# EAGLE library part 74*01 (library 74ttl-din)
Quad 2-input NAND gate, open collector

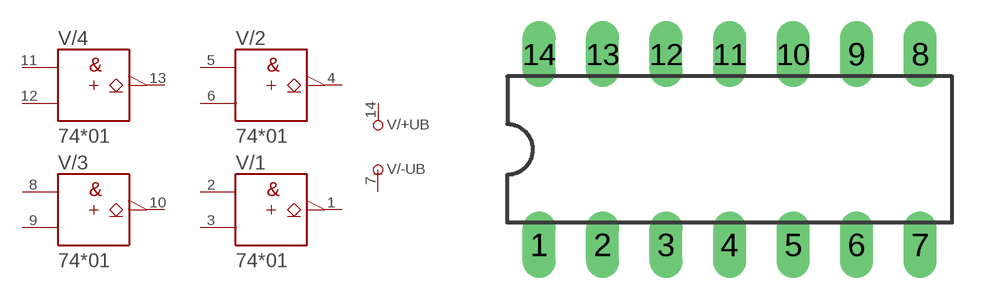
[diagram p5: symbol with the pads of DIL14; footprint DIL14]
Designator prefix V; gates /+UB=+UB /-UB=-UB /1=01 /2=01 /3=01 /4=01

## 7401N  [DIL14]
1  /1:Y  oc
2  /1:A  in
3  /1:B  in
4  /2:Y  oc
5  /2:A  in
6  /2:B  in
7  /-UB:-UB  pwr
8  /3:A  in
9  /3:B  in
10  /3:Y  oc
11  /4:A  in
12  /4:B  in
13  /4:Y  oc
14  /+UB:+UB  pwr

## Footprint DIL14 (pad centres in mm)
Dual In Line Package
drill 0.813 long: 1 -7.62,-3.81; 2 -5.08,-3.81; 3 -2.54,-3.81; 4 0,-3.81; 5 2.54,-3.81; 6 5.08,-3.81; 7 7.62,-3.81; 8 7.62,3.81; 9 5.08,3.81; 10 2.54,3.81; 11 0,3.81; 12 -2.54,3.81; 13 -5.08,3.81; 14 -7.62,3.81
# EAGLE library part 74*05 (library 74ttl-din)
Hex INVERTER, open collector

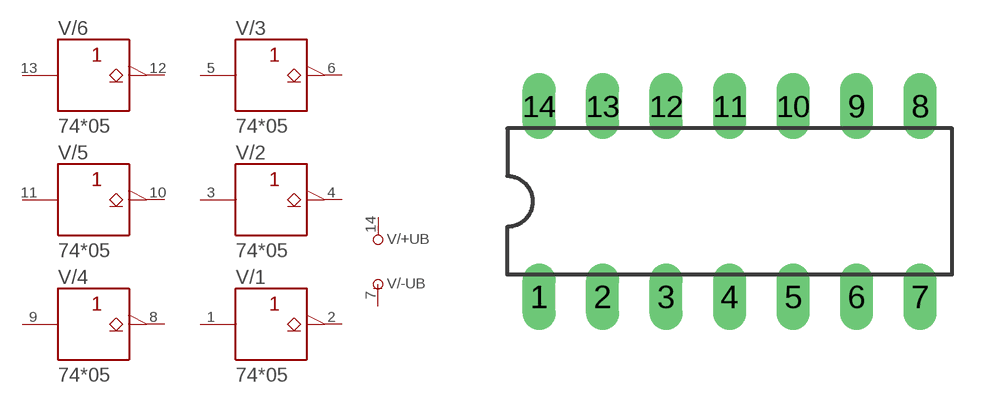
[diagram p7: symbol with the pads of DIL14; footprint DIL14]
Designator prefix V; gates /+UB=+UB /-UB=-UB /1=05 /2=05 /3=05 /4=05 /5=05 /6=05

## 7405N  [DIL14]
1  /1:A  in
2  /1:Y  oc
3  /2:A  in
4  /2:Y  oc
5  /3:A  in
6  /3:Y  oc
7  /-UB:-UB  pwr
8  /4:Y  oc
9  /4:A  in
10  /5:Y  oc
11  /5:A  in
12  /6:Y  oc
13  /6:A  in
14  /+UB:+UB  pwr

## Footprint DIL14 (pad centres in mm)
Dual In Line Package
drill 0.813 long: 1 -7.62,-3.81; 2 -5.08,-3.81; 3 -2.54,-3.81; 4 0,-3.81; 5 2.54,-3.81; 6 5.08,-3.81; 7 7.62,-3.81; 8 7.62,3.81; 9 5.08,3.81; 10 2.54,3.81; 11 0,3.81; 12 -2.54,3.81; 13 -5.08,3.81; 14 -7.62,3.81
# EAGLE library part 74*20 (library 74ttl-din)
Dual 4-input NAND gate

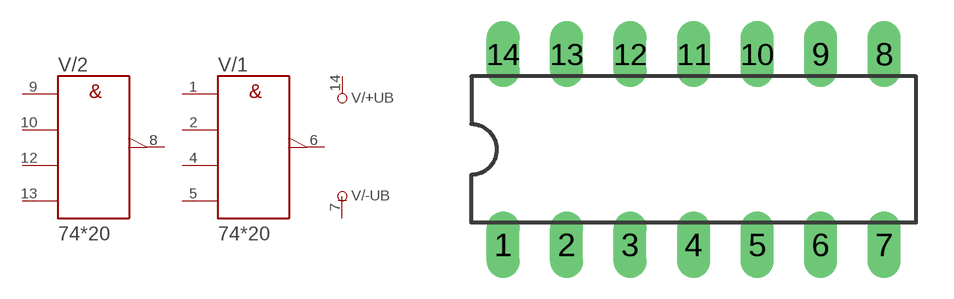
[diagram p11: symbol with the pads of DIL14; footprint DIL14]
Designator prefix V; gates /+UB=+UB /-UB=-UB /1=20 /2=20

## 7420N  [DIL14]
1  /1:A  in
2  /1:B  in
4  /1:C  in
5  /1:D  in
6  /1:Y  out
7  /-UB:-UB  pwr
8  /2:Y  out
9  /2:A  in
10  /2:B  in
12  /2:C  in
13  /2:D  in
14  /+UB:+UB  pwr

## Footprint DIL14 (pad centres in mm)
Dual In Line Package
drill 0.813 long: 1 -7.62,-3.81; 2 -5.08,-3.81; 3 -2.54,-3.81; 4 0,-3.81; 5 2.54,-3.81; 6 5.08,-3.81; 7 7.62,-3.81; 8 7.62,3.81; 9 5.08,3.81; 10 2.54,3.81; 11 0,3.81; 12 -2.54,3.81; 13 -5.08,3.81; 14 -7.62,3.81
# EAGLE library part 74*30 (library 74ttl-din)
8-input NAND gate

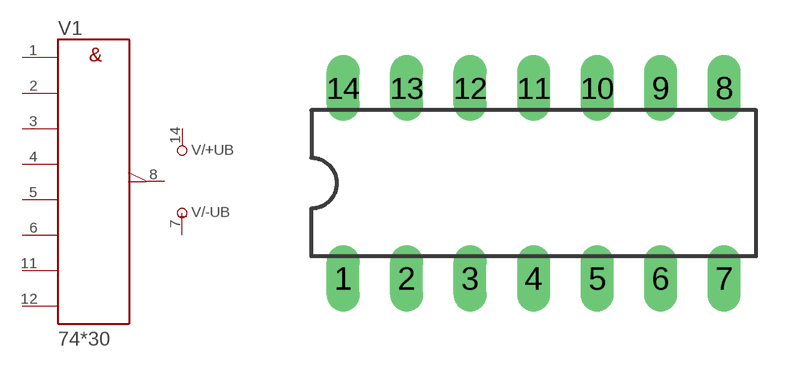
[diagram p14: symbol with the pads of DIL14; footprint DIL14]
Designator prefix V; gates /+UB=+UB /-UB=-UB 1=30

## 7430N  [DIL14]
1  1:A  in
2  1:B  in
3  1:C  in
4  1:D  in
5  1:E  in
6  1:F  in
7  /-UB:-UB  pwr
8  1:Y  out
11  1:G  in
12  1:H  in
14  /+UB:+UB  pwr

## Footprint DIL14 (pad centres in mm)
Dual In Line Package
drill 0.813 long: 1 -7.62,-3.81; 2 -5.08,-3.81; 3 -2.54,-3.81; 4 0,-3.81; 5 2.54,-3.81; 6 5.08,-3.81; 7 7.62,-3.81; 8 7.62,3.81; 9 5.08,3.81; 10 2.54,3.81; 11 0,3.81; 12 -2.54,3.81; 13 -5.08,3.81; 14 -7.62,3.81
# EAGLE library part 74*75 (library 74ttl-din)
4-bit bistable LATCH

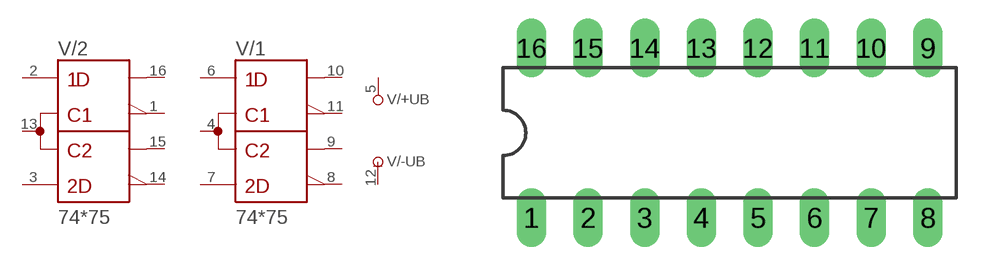
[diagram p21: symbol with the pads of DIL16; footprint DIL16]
Designator prefix V; gates /+UB=+UB /-UB=-UB /1=75 /2=75

## 7475N  [DIL16]
1  /2:!1Q  out
2  /2:1D  in
3  /2:2D  in
4  /1:1C,2C  in
5  /+UB:+UB  pwr
6  /1:1D  in
7  /1:2D  in
8  /1:!2Q  out
9  /1:2Q  out
10  /1:1Q  out
11  /1:!1Q  out
12  /-UB:-UB  pwr
13  /2:1C,2C  in
14  /2:!2Q  out
15  /2:2Q  out
16  /2:1Q  out

## Footprint DIL16 (pad centres in mm)
Dual In Line Package
drill 0.813 long: 1 -8.89,-3.81; 2 -6.35,-3.81; 3 -3.81,-3.81; 4 -1.27,-3.81; 5 1.27,-3.81; 6 3.81,-3.81; 7 6.35,-3.81; 8 8.89,-3.81; 9 8.89,3.81; 10 6.35,3.81; 11 3.81,3.81; 12 1.27,3.81; 13 -1.27,3.81; 14 -3.81,3.81; 15 -6.35,3.81; 16 -8.89,3.81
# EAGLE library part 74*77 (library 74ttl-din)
4-bit D LATCH

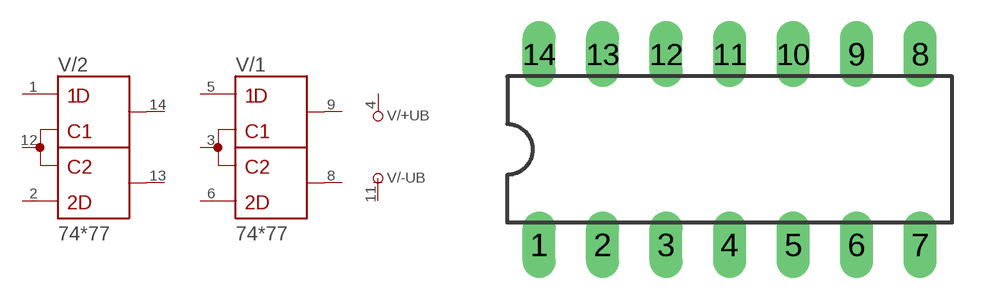
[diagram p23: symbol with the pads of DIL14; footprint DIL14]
Designator prefix V; gates /+UB=+UB /-UB=-UB /1=77 /2=77

## 7477N  [DIL14]
1  /2:1D  in
2  /2:2D  in
3  /1:1C,2C  in
4  /+UB:+UB  pwr
5  /1:1D  in
6  /1:2D  in
8  /1:2Q  out
9  /1:1Q  out
11  /-UB:-UB  pwr
12  /2:1C,2C  in
13  /2:2Q  out
14  /2:1Q  out

## Footprint DIL14 (pad centres in mm)
Dual In Line Package
drill 0.813 long: 1 -7.62,-3.81; 2 -5.08,-3.81; 3 -2.54,-3.81; 4 0,-3.81; 5 2.54,-3.81; 6 5.08,-3.81; 7 7.62,-3.81; 8 7.62,3.81; 9 5.08,3.81; 10 2.54,3.81; 11 0,3.81; 12 -2.54,3.81; 13 -5.08,3.81; 14 -7.62,3.81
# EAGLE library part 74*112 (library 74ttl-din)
Dual J-K negative edge triggered FLIP FLOP, preset and clear

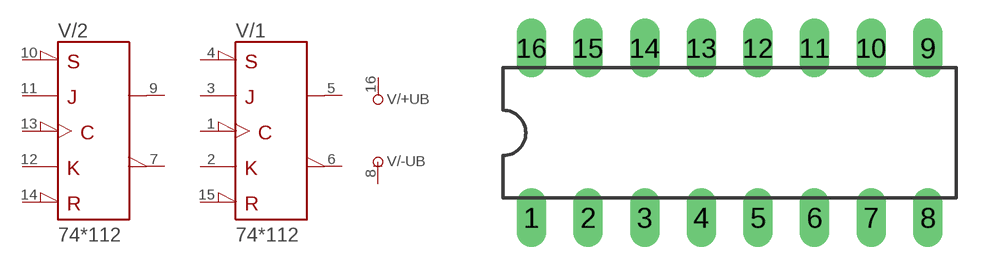
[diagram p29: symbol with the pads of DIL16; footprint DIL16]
Designator prefix V; gates /+UB=+UB /-UB=-UB /1=112 /2=112

## 74112N  [DIL16]
1  /1:CLK  in
2  /1:K  in
3  /1:J  in
4  /1:!PRE  in
5  /1:Q  out
6  /1:!Q  out
7  /2:!Q  out
8  /-UB:-UB  pwr
9  /2:Q  out
10  /2:!PRE  in
11  /2:J  in
12  /2:K  in
13  /2:CLK  in
14  /2:!CLR  in
15  /1:!CLR  in
16  /+UB:+UB  pwr

## Footprint DIL16 (pad centres in mm)
Dual In Line Package
drill 0.813 long: 1 -8.89,-3.81; 2 -6.35,-3.81; 3 -3.81,-3.81; 4 -1.27,-3.81; 5 1.27,-3.81; 6 3.81,-3.81; 7 6.35,-3.81; 8 8.89,-3.81; 9 8.89,3.81; 10 6.35,3.81; 11 3.81,3.81; 12 1.27,3.81; 13 -1.27,3.81; 14 -3.81,3.81; 15 -6.35,3.81; 16 -8.89,3.81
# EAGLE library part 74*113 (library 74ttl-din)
Dual J-K negative edge triggered FLIP FLOP, preset

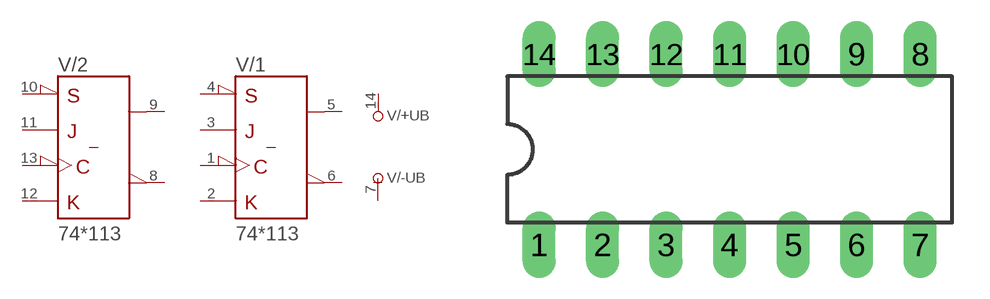
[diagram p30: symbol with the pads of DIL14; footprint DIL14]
Designator prefix V; gates /+UB=+UB /-UB=-UB /1=113 /2=113

## 74113N  [DIL14]
1  /1:CLK  in
2  /1:K  in
3  /1:J  in
4  /1:!PRE  in
5  /1:Q  out
6  /1:!Q  out
7  /-UB:-UB  pwr
8  /2:!Q  out
9  /2:Q  out
10  /2:!PRE  in
11  /2:J  in
12  /2:K  in
13  /2:CLK  in
14  /+UB:+UB  pwr

## Footprint DIL14 (pad centres in mm)
Dual In Line Package
drill 0.813 long: 1 -7.62,-3.81; 2 -5.08,-3.81; 3 -2.54,-3.81; 4 0,-3.81; 5 2.54,-3.81; 6 5.08,-3.81; 7 7.62,-3.81; 8 7.62,3.81; 9 5.08,3.81; 10 2.54,3.81; 11 0,3.81; 12 -2.54,3.81; 13 -5.08,3.81; 14 -7.62,3.81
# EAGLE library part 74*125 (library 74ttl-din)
Quad bus BUFFER, 3-state

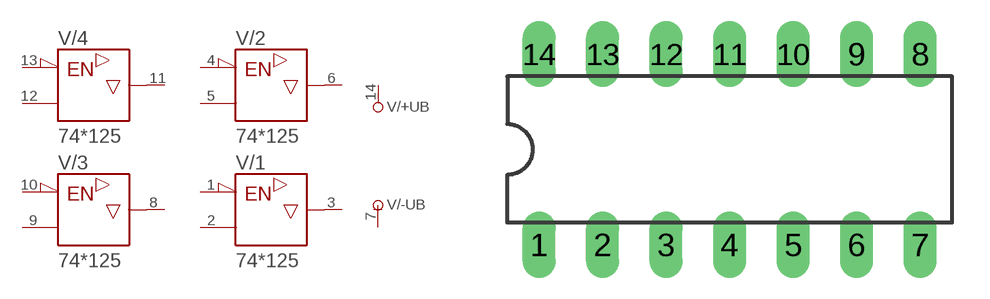
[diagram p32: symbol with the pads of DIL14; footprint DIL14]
Designator prefix V; gates /+UB=+UB /-UB=-UB /1=125 /2=125 /3=125 /4=125

## 74125N  [DIL14]
1  /1:!G  in
2  /1:A  in
3  /1:Y  hiz
4  /2:!G  in
5  /2:A  in
6  /2:Y  hiz
7  /-UB:-UB  pwr
8  /3:Y  hiz
9  /3:A  in
10  /3:!G  in
11  /4:Y  hiz
12  /4:A  in
13  /4:!G  in
14  /+UB:+UB  pwr

## Footprint DIL14 (pad centres in mm)
Dual In Line Package
drill 0.813 long: 1 -7.62,-3.81; 2 -5.08,-3.81; 3 -2.54,-3.81; 4 0,-3.81; 5 2.54,-3.81; 6 5.08,-3.81; 7 7.62,-3.81; 8 7.62,3.81; 9 5.08,3.81; 10 2.54,3.81; 11 0,3.81; 12 -2.54,3.81; 13 -5.08,3.81; 14 -7.62,3.81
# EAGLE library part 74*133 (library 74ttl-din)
13-input NAND gate

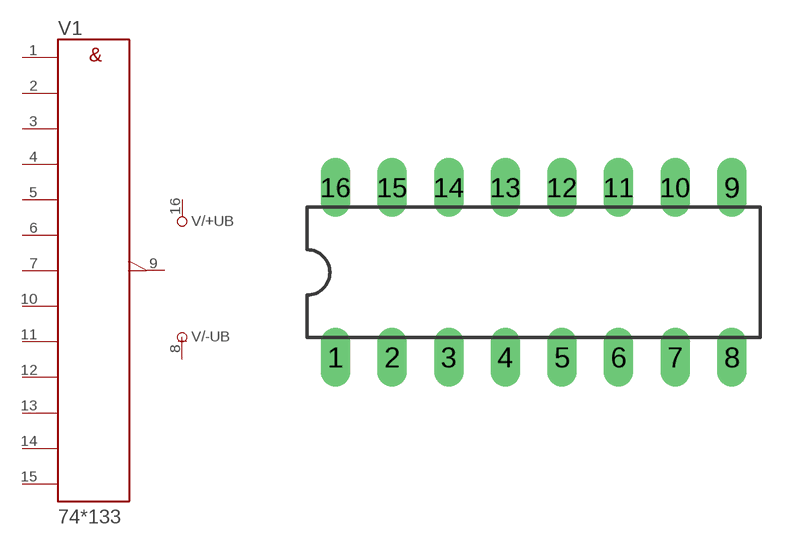
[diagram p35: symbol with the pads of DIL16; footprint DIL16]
Designator prefix V; gates /+UB=+UB /-UB=-UB 1=133

## 74133N  [DIL16]
1  1:A  in
2  1:B  in
3  1:C  in
4  1:D  in
5  1:E  in
6  1:F  in
7  1:G  in
8  /-UB:-UB  pwr
9  1:Y  out
10  1:H  in
11  1:I  in
12  1:J  in
13  1:K  in
14  1:L  in
15  1:M  in
16  /+UB:+UB  pwr

## Footprint DIL16 (pad centres in mm)
Dual In Line Package
drill 0.813 long: 1 -8.89,-3.81; 2 -6.35,-3.81; 3 -3.81,-3.81; 4 -1.27,-3.81; 5 1.27,-3.81; 6 3.81,-3.81; 7 6.35,-3.81; 8 8.89,-3.81; 9 8.89,3.81; 10 6.35,3.81; 11 3.81,3.81; 12 1.27,3.81; 13 -1.27,3.81; 14 -3.81,3.81; 15 -6.35,3.81; 16 -8.89,3.81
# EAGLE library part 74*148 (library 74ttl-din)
10-line to 4-line and 8-line to 3-line PRIORITY ENCODER

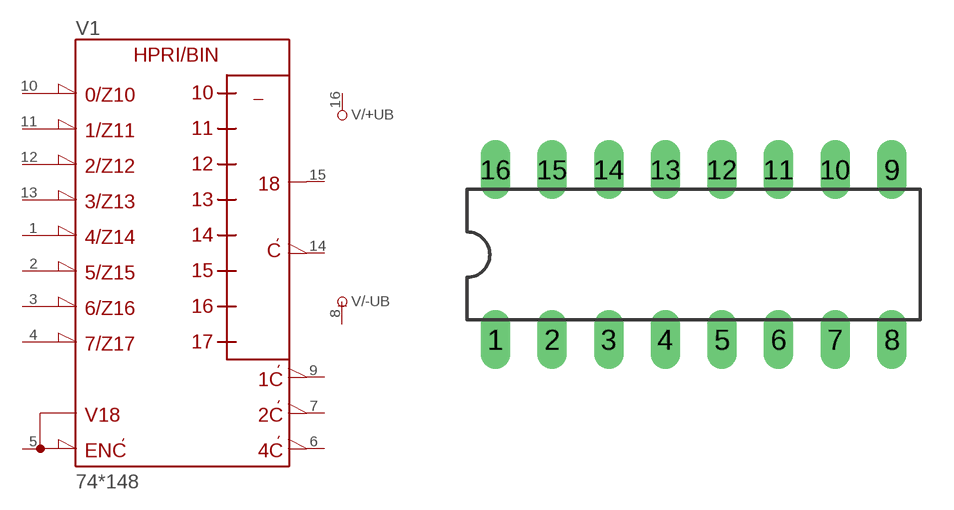
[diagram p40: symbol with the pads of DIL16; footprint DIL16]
Designator prefix V; gates /+UB=+UB /-UB=-UB 1=148

## 74148N  [DIL16]
1  1:4  in
2  1:5  in
3  1:6  in
4  1:7  in
5  1:EI  in
6  1:A2  out
7  1:A1  out
8  /-UB:-UB  pwr
9  1:A0  out
10  1:0  in
11  1:1  in
12  1:2  in
13  1:3  in
14  1:GS  out
15  1:EO  out
16  /+UB:+UB  pwr

## Footprint DIL16 (pad centres in mm)
Dual In Line Package
drill 0.813 long: 1 -8.89,-3.81; 2 -6.35,-3.81; 3 -3.81,-3.81; 4 -1.27,-3.81; 5 1.27,-3.81; 6 3.81,-3.81; 7 6.35,-3.81; 8 8.89,-3.81; 9 8.89,3.81; 10 6.35,3.81; 11 3.81,3.81; 12 1.27,3.81; 13 -1.27,3.81; 14 -3.81,3.81; 15 -6.35,3.81; 16 -8.89,3.81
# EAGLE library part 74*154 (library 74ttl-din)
4-line to 16-line data SELECTOR/MULTIPLEXER

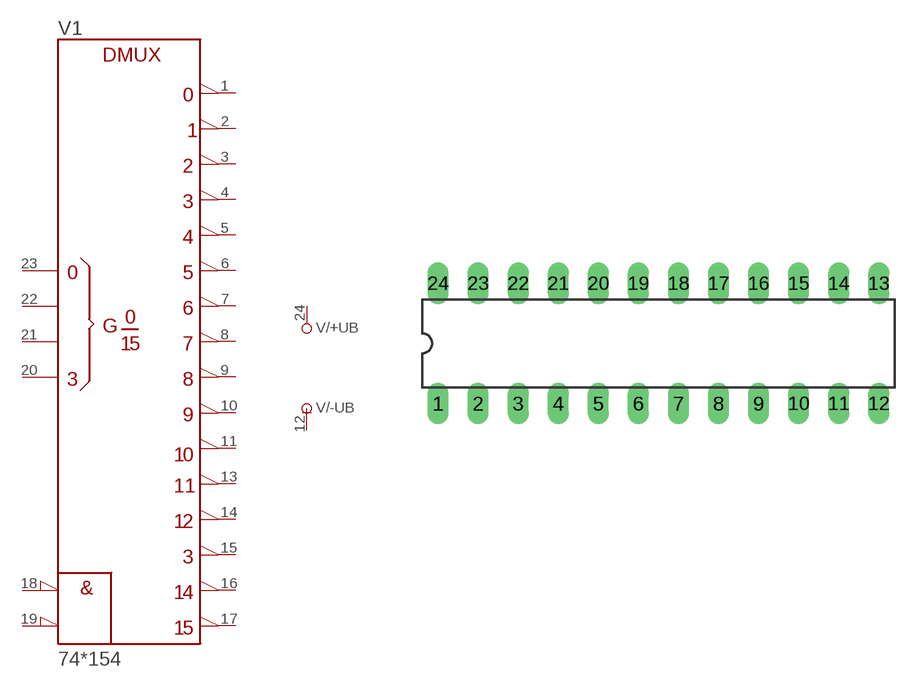
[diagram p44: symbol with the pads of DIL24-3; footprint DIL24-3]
Designator prefix V; gates /+UB=+UB /-UB=-UB 1=154

## 74154N  [DIL24-3]
1  1:0  out
2  1:1  out
3  1:2  out
4  1:3  out
5  1:4  out
6  1:5  out
7  1:6  out
8  1:7  out
9  1:8  out
10  1:9  out
11  1:10  out
12  /-UB:-UB  pwr
13  1:11  out
14  1:12  out
15  1:13  out
16  1:14  out
17  1:15  out
18  1:!G1  in
19  1:!G2  in
20  1:D  in
21  1:C  in
22  1:B  in
23  1:A  in
24  /+UB:+UB  pwr

## Footprint DIL24-3 (pad centres in mm)
Dual In Line Package 0.3 inch
drill 0.813 long: 1 -13.97,-3.81; 2 -11.43,-3.81; 3 -8.89,-3.81; 4 -6.35,-3.81; 5 -3.81,-3.81; 6 -1.27,-3.81; 7 1.27,-3.81; 8 3.81,-3.81; 9 6.35,-3.81; 10 8.89,-3.81; 11 11.43,-3.81; 12 13.97,-3.81; 13 13.97,3.81; 14 11.43,3.81; 15 8.89,3.81; 16 6.35,3.81; 17 3.81,3.81; 18 1.27,3.81; 19 -1.27,3.81; 20 -3.81,3.81; 21 -6.35,3.81; 22 -8.89,3.81; 23 -11.43,3.81; 24 -13.97,3.81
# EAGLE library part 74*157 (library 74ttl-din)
Quadruple 2-line to 1-line data SELECTOR/MULTIPLEXER

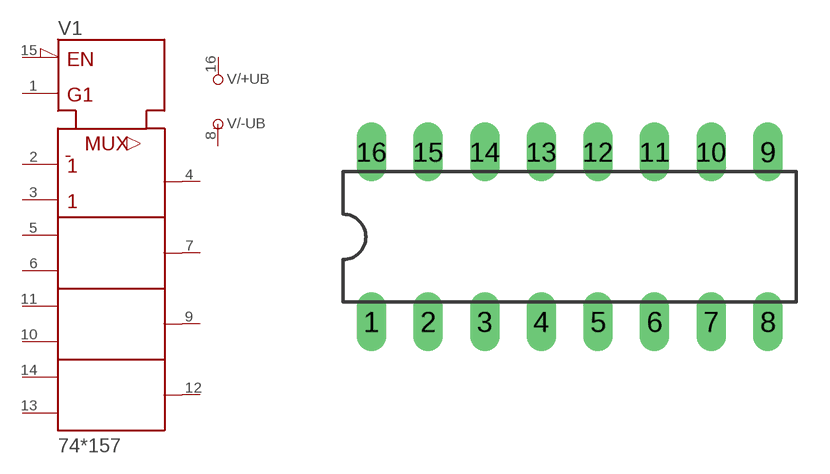
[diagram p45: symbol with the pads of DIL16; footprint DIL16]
Designator prefix V; gates /+UB=+UB /-UB=-UB 1=157

## 74157N  [DIL16]
1  1:!A!/B  in
2  1:1A  in
3  1:1B  in
4  1:1Y  out
5  1:2A  in
6  1:2B  in
7  1:2Y  out
8  /-UB:-UB  pwr
9  1:3Y  out
10  1:3B  in
11  1:3A  in
12  1:4Y  out
13  1:4B  in
14  1:4A  in
15  1:!G  in
16  /+UB:+UB  pwr

## Footprint DIL16 (pad centres in mm)
Dual In Line Package
drill 0.813 long: 1 -8.89,-3.81; 2 -6.35,-3.81; 3 -3.81,-3.81; 4 -1.27,-3.81; 5 1.27,-3.81; 6 3.81,-3.81; 7 6.35,-3.81; 8 8.89,-3.81; 9 8.89,3.81; 10 6.35,3.81; 11 3.81,3.81; 12 1.27,3.81; 13 -1.27,3.81; 14 -3.81,3.81; 15 -6.35,3.81; 16 -8.89,3.81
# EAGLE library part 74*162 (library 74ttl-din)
Synchrounus 4-bit COUNTER divide by 10

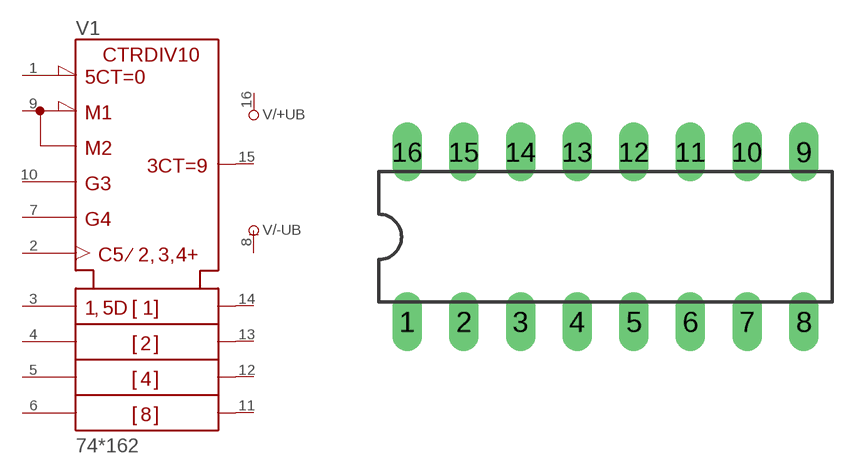
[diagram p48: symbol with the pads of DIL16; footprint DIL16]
Designator prefix V; gates /+UB=+UB /-UB=-UB 1=162

## 74162N  [DIL16]
1  1:!CLR  in
2  1:CLK  in
3  1:A  in
4  1:B  in
5  1:C  in
6  1:D  in
7  1:ENP  in
8  /-UB:-UB  pwr
9  1:!LOAD  in
10  1:ENT  in
11  1:QD  out
12  1:QC  out
13  1:QB  out
14  1:QA  out
15  1:RCO  out
16  /+UB:+UB  pwr

## Footprint DIL16 (pad centres in mm)
Dual In Line Package
drill 0.813 long: 1 -8.89,-3.81; 2 -6.35,-3.81; 3 -3.81,-3.81; 4 -1.27,-3.81; 5 1.27,-3.81; 6 3.81,-3.81; 7 6.35,-3.81; 8 8.89,-3.81; 9 8.89,3.81; 10 6.35,3.81; 11 3.81,3.81; 12 1.27,3.81; 13 -1.27,3.81; 14 -3.81,3.81; 15 -6.35,3.81; 16 -8.89,3.81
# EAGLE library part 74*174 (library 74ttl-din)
Hex D type FLIP FLOP, clear

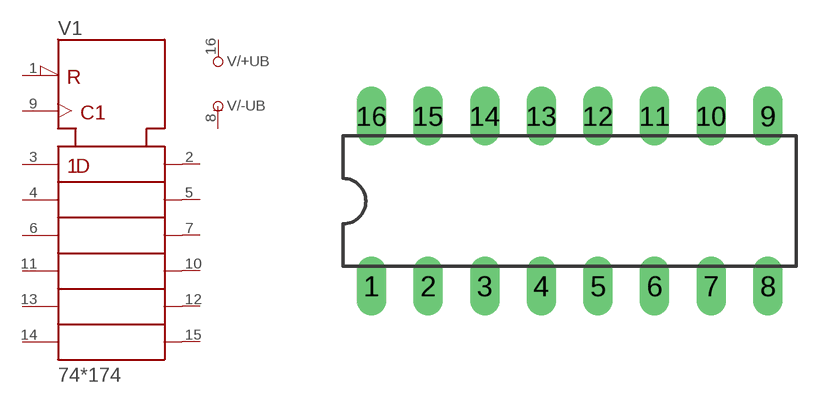
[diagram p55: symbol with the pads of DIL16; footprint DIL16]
Designator prefix V; gates /+UB=+UB /-UB=-UB 1=174

## 74174N  [DIL16]
1  1:!CLR  in
2  1:1Q  out
3  1:1D  in
4  1:2D  in
5  1:2Q  out
6  1:3D  in
7  1:3Q  out
8  /-UB:-UB  pwr
9  1:CLK  in
10  1:4Q  out
11  1:4D  in
12  1:5Q  out
13  1:5D  in
14  1:6D  in
15  1:6Q  out
16  /+UB:+UB  pwr

## Footprint DIL16 (pad centres in mm)
Dual In Line Package
drill 0.813 long: 1 -8.89,-3.81; 2 -6.35,-3.81; 3 -3.81,-3.81; 4 -1.27,-3.81; 5 1.27,-3.81; 6 3.81,-3.81; 7 6.35,-3.81; 8 8.89,-3.81; 9 8.89,3.81; 10 6.35,3.81; 11 3.81,3.81; 12 1.27,3.81; 13 -1.27,3.81; 14 -3.81,3.81; 15 -6.35,3.81; 16 -8.89,3.81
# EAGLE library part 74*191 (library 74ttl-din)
Synchronous up down COUNTER

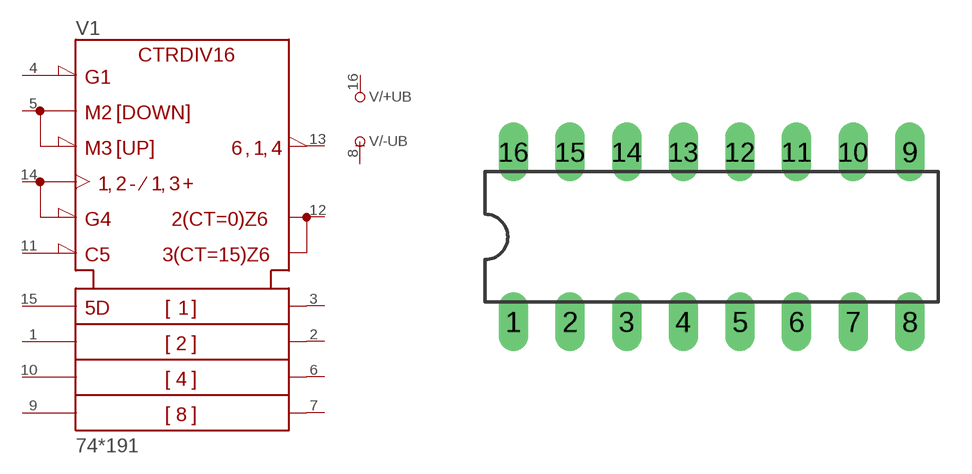
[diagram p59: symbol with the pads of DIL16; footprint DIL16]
Designator prefix V; gates /+UB=+UB /-UB=-UB 1=191

## 74191N  [DIL16]
1  1:B  in
2  1:QB  out
3  1:QA  out
4  1:!CTEN  in
5  1:D/!U  in
6  1:QC  out
7  1:QD  out
8  /-UB:-UB  pwr
9  1:D  in
10  1:C  in
11  1:!LOAD  in
12  1:MAX/MIN  out
13  1:!RCO  out
14  1:CLK  in
15  1:A  in
16  /+UB:+UB  pwr

## Footprint DIL16 (pad centres in mm)
Dual In Line Package
drill 0.813 long: 1 -8.89,-3.81; 2 -6.35,-3.81; 3 -3.81,-3.81; 4 -1.27,-3.81; 5 1.27,-3.81; 6 3.81,-3.81; 7 6.35,-3.81; 8 8.89,-3.81; 9 8.89,3.81; 10 6.35,3.81; 11 3.81,3.81; 12 1.27,3.81; 13 -1.27,3.81; 14 -3.81,3.81; 15 -6.35,3.81; 16 -8.89,3.81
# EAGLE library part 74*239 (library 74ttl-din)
Dual 1 of 4 noninverting DECODER/DEMULTIPLEXER

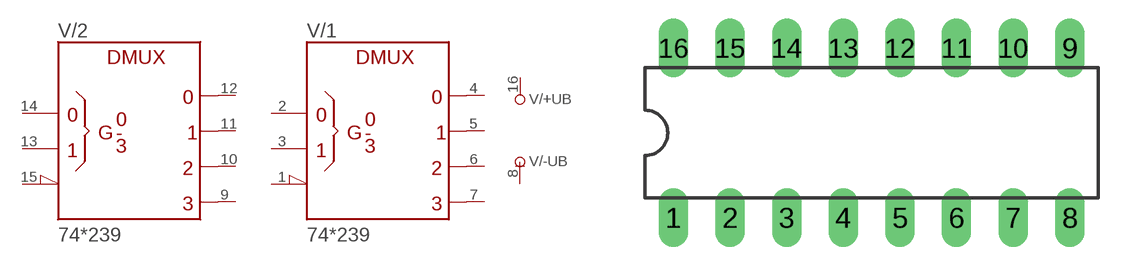
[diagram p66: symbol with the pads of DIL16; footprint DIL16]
Designator prefix V; gates /+UB=+UB /-UB=-UB /1=239 /2=239

## 74239N  [DIL16]
1  /1:!G  in
2  /1:A  in
3  /1:B  in
4  /1:Y0  out
5  /1:Y1  out
6  /1:Y2  out
7  /1:Y3  out
8  /-UB:-UB  pwr
9  /2:Y3  out
10  /2:Y2  out
11  /2:Y1  out
12  /2:Y0  out
13  /2:B  in
14  /2:A  in
15  /2:!G  in
16  /+UB:+UB  pwr

## Footprint DIL16 (pad centres in mm)
Dual In Line Package
drill 0.813 long: 1 -8.89,-3.81; 2 -6.35,-3.81; 3 -3.81,-3.81; 4 -1.27,-3.81; 5 1.27,-3.81; 6 3.81,-3.81; 7 6.35,-3.81; 8 8.89,-3.81; 9 8.89,3.81; 10 6.35,3.81; 11 3.81,3.81; 12 1.27,3.81; 13 -1.27,3.81; 14 -3.81,3.81; 15 -6.35,3.81; 16 -8.89,3.81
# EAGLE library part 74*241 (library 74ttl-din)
Octal BUFFER and LINE DRIVER, 3-state

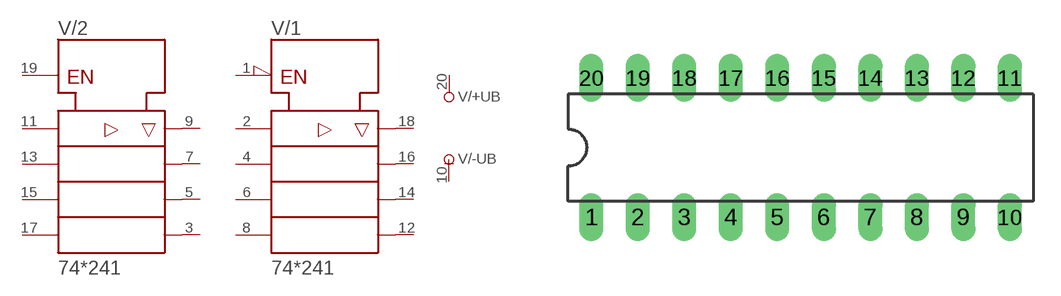
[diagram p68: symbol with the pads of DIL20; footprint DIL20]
Designator prefix V; gates /+UB=+UB /-UB=-UB /1=241_1 /2=241_2

## 74241N  [DIL20]
1  /1:!G  in
2  /1:A1  in
3  /2:Y4  hiz
4  /1:A2  in
5  /2:Y3  hiz
6  /1:A3  in
7  /2:Y2  hiz
8  /1:A4  in
9  /2:Y1  hiz
10  /-UB:-UB  pwr
11  /2:A1  in
12  /1:Y4  hiz
13  /2:A2  in
14  /1:Y3  hiz
15  /2:A3  in
16  /1:Y2  hiz
17  /2:A4  in
18  /1:Y1  hiz
19  /2:G  in
20  /+UB:+UB  pwr

## Footprint DIL20 (pad centres in mm)
Dual In Line Package
drill 0.813 long: 1 -11.43,-3.81; 2 -8.89,-3.81; 3 -6.35,-3.81; 4 -3.81,-3.81; 5 -1.27,-3.81; 6 1.27,-3.81; 7 3.81,-3.81; 8 6.35,-3.81; 9 8.89,-3.81; 10 11.43,-3.81; 11 11.43,3.81; 12 8.89,3.81; 13 6.35,3.81; 14 3.81,3.81; 15 1.27,3.81; 16 -1.27,3.81; 17 -3.81,3.81; 18 -6.35,3.81; 19 -8.89,3.81; 20 -11.43,3.81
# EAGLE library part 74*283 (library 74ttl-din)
4-bit binary FULL ADDER, fast carry

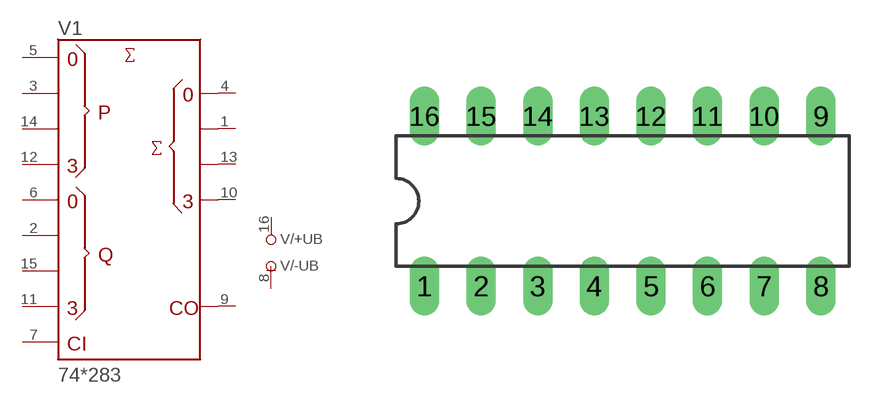
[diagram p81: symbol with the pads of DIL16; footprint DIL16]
Designator prefix V; gates /+UB=+UB /-UB=-UB 1=283

## 74283N  [DIL16]
1  1:S2  out
2  1:B2  in
3  1:A2  in
4  1:S1  out
5  1:A1  in
6  1:B1  in
7  1:C0  in
8  /-UB:-UB  pwr
9  1:C4  out
10  1:S4  out
11  1:B4  in
12  1:A4  in
13  1:S3  out
14  1:A3  in
15  1:B3  in
16  /+UB:+UB  pwr

## Footprint DIL16 (pad centres in mm)
Dual In Line Package
drill 0.813 long: 1 -8.89,-3.81; 2 -6.35,-3.81; 3 -3.81,-3.81; 4 -1.27,-3.81; 5 1.27,-3.81; 6 3.81,-3.81; 7 6.35,-3.81; 8 8.89,-3.81; 9 8.89,3.81; 10 6.35,3.81; 11 3.81,3.81; 12 1.27,3.81; 13 -1.27,3.81; 14 -3.81,3.81; 15 -6.35,3.81; 16 -8.89,3.81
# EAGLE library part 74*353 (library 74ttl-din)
Dual 4-to 1 line data SELECTOR/MULTIPLEXER, 3-state

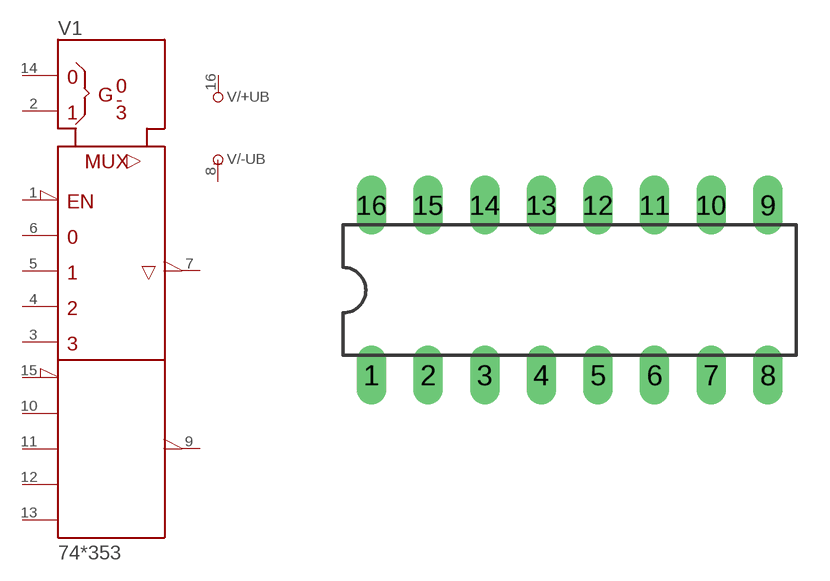
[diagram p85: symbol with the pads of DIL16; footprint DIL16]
Designator prefix V; gates /+UB=+UB /-UB=-UB 1=353

## 74353N  [DIL16]
1  1:!1G  in
2  1:B  in
3  1:1C3  in
4  1:1C2  in
5  1:1C1  in
6  1:1C0  in
7  1:1Y  hiz
8  /-UB:-UB  pwr
9  1:2Y  hiz
10  1:2C0  in
11  1:2C1  in
12  1:2C2  in
13  1:2C3  in
14  1:A  in
15  1:!2G  in
16  /+UB:+UB  pwr

## Footprint DIL16 (pad centres in mm)
Dual In Line Package
drill 0.813 long: 1 -8.89,-3.81; 2 -6.35,-3.81; 3 -3.81,-3.81; 4 -1.27,-3.81; 5 1.27,-3.81; 6 3.81,-3.81; 7 6.35,-3.81; 8 8.89,-3.81; 9 8.89,3.81; 10 6.35,3.81; 11 3.81,3.81; 12 1.27,3.81; 13 -1.27,3.81; 14 -3.81,3.81; 15 -6.35,3.81; 16 -8.89,3.81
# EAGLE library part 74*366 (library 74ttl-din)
Hex BUS DRIVER, 3-state

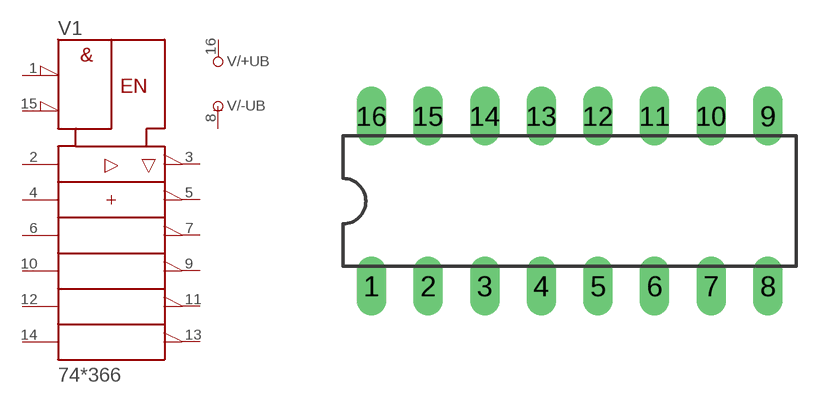
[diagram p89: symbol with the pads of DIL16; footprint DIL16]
Designator prefix V; gates /+UB=+UB /-UB=-UB 1=366

## 74366N  [DIL16]
1  1:!G1  in
2  1:A1  in
3  1:Y1  hiz
4  1:A2  in
5  1:Y2  hiz
6  1:A3  in
7  1:Y3  hiz
8  /-UB:-UB  pwr
9  1:Y4  hiz
10  1:A4  in
11  1:Y5  hiz
12  1:A5  in
13  1:Y6  hiz
14  1:A6  in
15  1:!G2  in
16  /+UB:+UB  pwr

## Footprint DIL16 (pad centres in mm)
Dual In Line Package
drill 0.813 long: 1 -8.89,-3.81; 2 -6.35,-3.81; 3 -3.81,-3.81; 4 -1.27,-3.81; 5 1.27,-3.81; 6 3.81,-3.81; 7 6.35,-3.81; 8 8.89,-3.81; 9 8.89,3.81; 10 6.35,3.81; 11 3.81,3.81; 12 1.27,3.81; 13 -1.27,3.81; 14 -3.81,3.81; 15 -6.35,3.81; 16 -8.89,3.81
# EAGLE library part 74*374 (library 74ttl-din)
Octal D type transparent LATCH, edge triggered

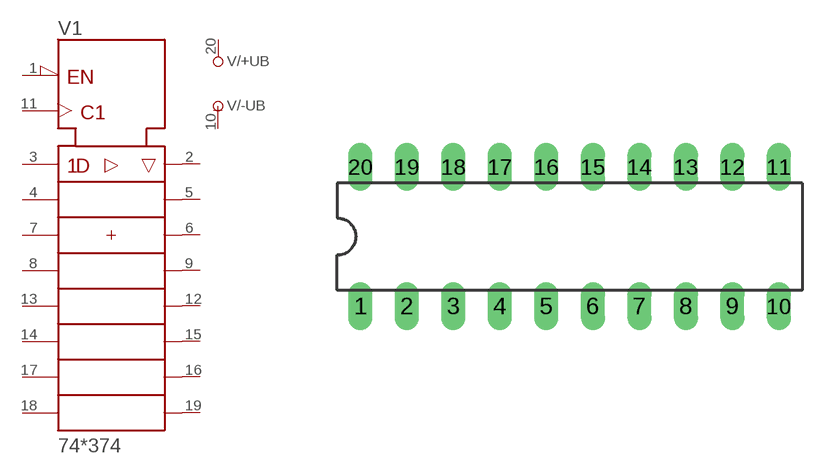
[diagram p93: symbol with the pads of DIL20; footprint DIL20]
Designator prefix V; gates /+UB=+UB /-UB=-UB 1=374

## 74374N  [DIL20]
1  1:!OC  in
2  1:1Q  hiz
3  1:1D  in
4  1:2D  in
5  1:2Q  hiz
6  1:3Q  hiz
7  1:3D  in
8  1:4D  in
9  1:4Q  hiz
10  /-UB:-UB  pwr
11  1:CLK  in
12  1:5Q  hiz
13  1:5D  in
14  1:6D  in
15  1:6Q  hiz
16  1:7Q  hiz
17  1:7D  in
18  1:8D  in
19  1:8Q  hiz
20  /+UB:+UB  pwr

## Footprint DIL20 (pad centres in mm)
Dual In Line Package
drill 0.813 long: 1 -11.43,-3.81; 2 -8.89,-3.81; 3 -6.35,-3.81; 4 -3.81,-3.81; 5 -1.27,-3.81; 6 1.27,-3.81; 7 3.81,-3.81; 8 6.35,-3.81; 9 8.89,-3.81; 10 11.43,-3.81; 11 11.43,3.81; 12 8.89,3.81; 13 6.35,3.81; 14 3.81,3.81; 15 1.27,3.81; 16 -1.27,3.81; 17 -3.81,3.81; 18 -6.35,3.81; 19 -8.89,3.81; 20 -11.43,3.81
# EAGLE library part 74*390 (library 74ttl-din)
Dual 4-bit decade and binary COUNTER

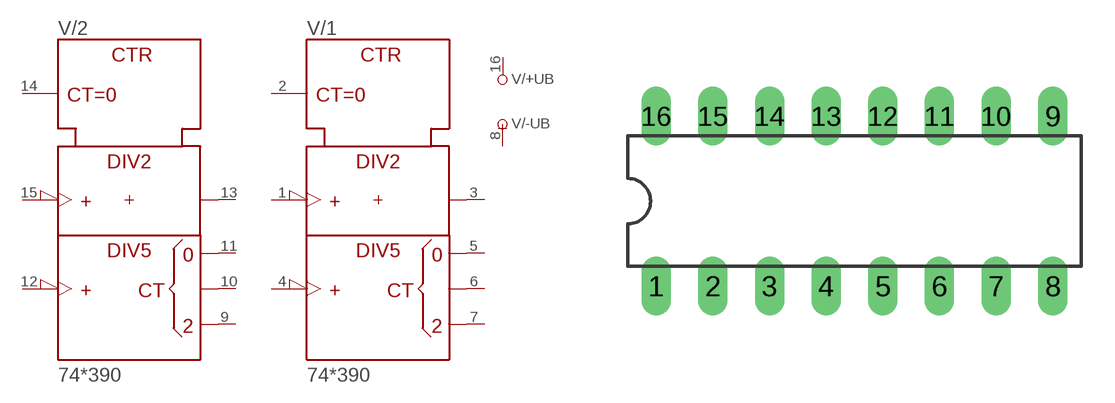
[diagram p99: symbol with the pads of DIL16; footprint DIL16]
Designator prefix V; gates /+UB=+UB /-UB=-UB /1=390 /2=390

## 74390N  [DIL16]
1  /1:CKA  in
2  /1:CLR  in
3  /1:QA  out
4  /1:CKB  in
5  /1:QB  out
6  /1:QC  out
7  /1:QD  out
8  /-UB:-UB  pwr
9  /2:QD  out
10  /2:QC  out
11  /2:QB  out
12  /2:CKB  in
13  /2:QA  out
14  /2:CLR  in
15  /2:CKA  in
16  /+UB:+UB  pwr

## Footprint DIL16 (pad centres in mm)
Dual In Line Package
drill 0.813 long: 1 -8.89,-3.81; 2 -6.35,-3.81; 3 -3.81,-3.81; 4 -1.27,-3.81; 5 1.27,-3.81; 6 3.81,-3.81; 7 6.35,-3.81; 8 8.89,-3.81; 9 8.89,3.81; 10 6.35,3.81; 11 3.81,3.81; 12 1.27,3.81; 13 -1.27,3.81; 14 -3.81,3.81; 15 -6.35,3.81; 16 -8.89,3.81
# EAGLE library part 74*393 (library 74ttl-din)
Dual 4-bit decade and binary COUNTER

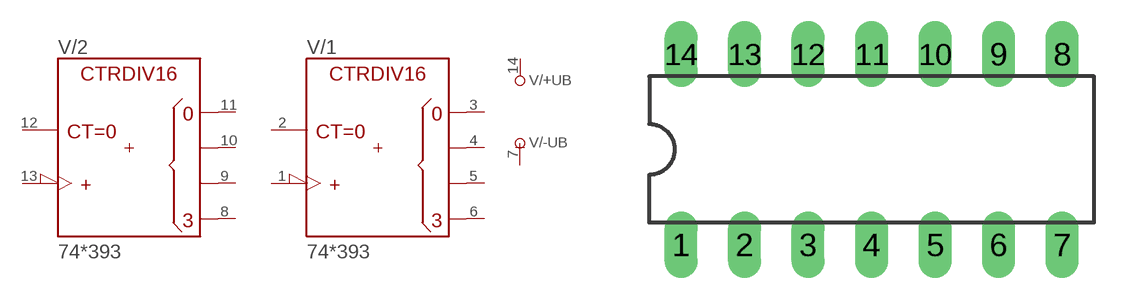
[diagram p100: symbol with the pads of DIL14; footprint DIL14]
Designator prefix V; gates /+UB=+UB /-UB=-UB /1=393 /2=393

## 74393N  [DIL14]
1  /1:A  in
2  /1:CLR  in
3  /1:QA  out
4  /1:QB  out
5  /1:QC  out
6  /1:QD  out
7  /-UB:-UB  pwr
8  /2:QD  out
9  /2:QC  out
10  /2:QB  out
11  /2:QA  out
12  /2:CLR  in
13  /2:A  in
14  /+UB:+UB  pwr

## Footprint DIL14 (pad centres in mm)
Dual In Line Package
drill 0.813 long: 1 -7.62,-3.81; 2 -5.08,-3.81; 3 -2.54,-3.81; 4 0,-3.81; 5 2.54,-3.81; 6 5.08,-3.81; 7 7.62,-3.81; 8 7.62,3.81; 9 5.08,3.81; 10 2.54,3.81; 11 0,3.81; 12 -2.54,3.81; 13 -5.08,3.81; 14 -7.62,3.81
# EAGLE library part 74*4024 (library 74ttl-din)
7-bit asynchronous binary COUNTER

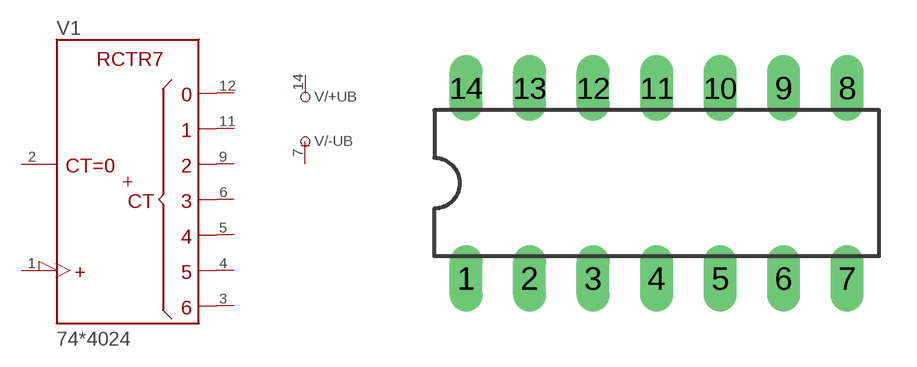
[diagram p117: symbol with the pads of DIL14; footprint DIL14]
Designator prefix V; gates /+UB=+UB /-UB=-UB 1=4024

## 744024N  [DIL14]
1  1:CLK  in
2  1:CLR  in
3  1:QG  out
4  1:QF  out
5  1:QE  out
6  1:QD  out
7  /-UB:-UB  pwr
9  1:QC  out
11  1:QB  out
12  1:QA  out
14  /+UB:+UB  pwr

## Footprint DIL14 (pad centres in mm)
Dual In Line Package
drill 0.813 long: 1 -7.62,-3.81; 2 -5.08,-3.81; 3 -2.54,-3.81; 4 0,-3.81; 5 2.54,-3.81; 6 5.08,-3.81; 7 7.62,-3.81; 8 7.62,3.81; 9 5.08,3.81; 10 2.54,3.81; 11 0,3.81; 12 -2.54,3.81; 13 -5.08,3.81; 14 -7.62,3.81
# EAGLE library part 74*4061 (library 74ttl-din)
14-bit asynchronous binary COUNTER

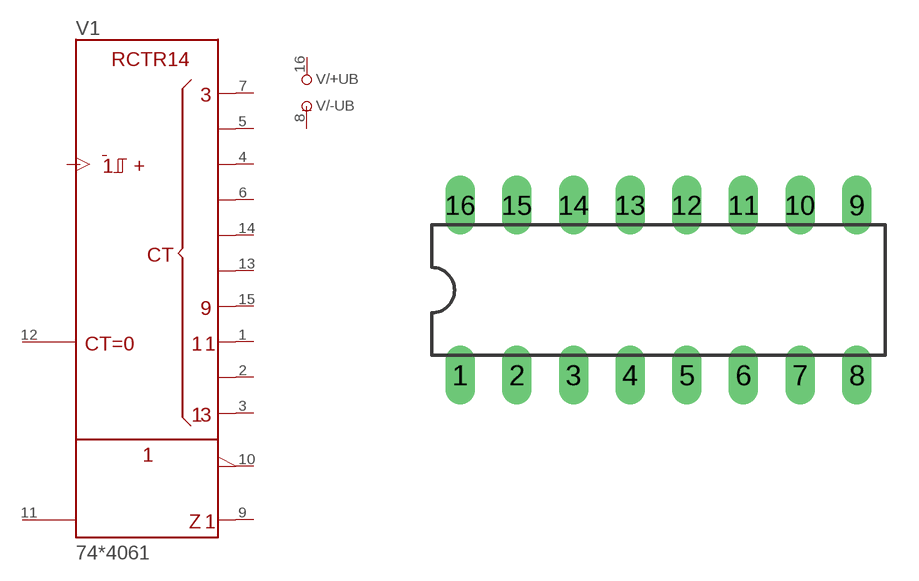
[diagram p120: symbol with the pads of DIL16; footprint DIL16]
Designator prefix V; gates /+UB=+UB /-UB=-UB 1=4061

## 744061N  [DIL16]
1  1:QL  out
2  1:QM  out
3  1:QN  out
4  1:QF  out
5  1:QE  out
6  1:QG  out
7  1:QD  out
8  /-UB:-UB  pwr
9  1:CKO  out
10  1:!CKO  out
11  1:CKI  in
12  1:CLR  in
13  1:QI  out
14  1:QH  out
15  1:QJ  out
16  /+UB:+UB  pwr

## Footprint DIL16 (pad centres in mm)
Dual In Line Package
drill 0.813 long: 1 -8.89,-3.81; 2 -6.35,-3.81; 3 -3.81,-3.81; 4 -1.27,-3.81; 5 1.27,-3.81; 6 3.81,-3.81; 7 6.35,-3.81; 8 8.89,-3.81; 9 8.89,3.81; 10 6.35,3.81; 11 3.81,3.81; 12 1.27,3.81; 13 -1.27,3.81; 14 -3.81,3.81; 15 -6.35,3.81; 16 -8.89,3.81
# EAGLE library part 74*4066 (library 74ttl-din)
Quad analog SWITCH

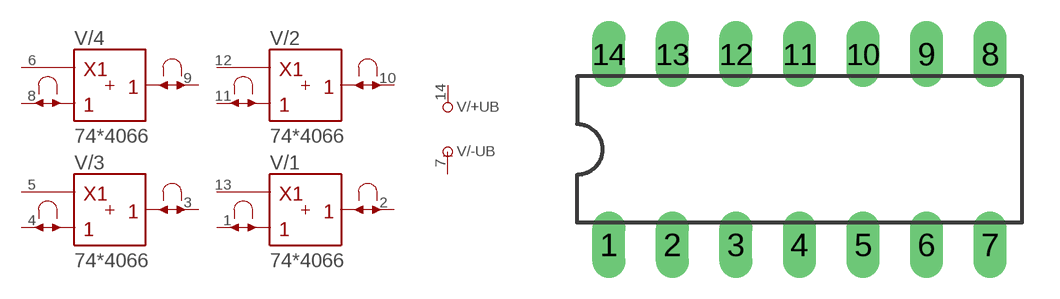
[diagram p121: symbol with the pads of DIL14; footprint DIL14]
Designator prefix V; gates /+UB=+UB /-UB=-UB /1=4066 /2=4066 /3=4066 /4=4066

## 744066N  [DIL14]
1  /1:A  pas
2  /1:B  pas
3  /3:B  pas
4  /3:A  pas
5  /3:C  in
6  /4:C  in
7  /-UB:-UB  pwr
8  /4:A  pas
9  /4:B  pas
10  /2:B  pas
11  /2:A  pas
12  /2:C  in
13  /1:C  in
14  /+UB:+UB  pwr

## Footprint DIL14 (pad centres in mm)
Dual In Line Package
drill 0.813 long: 1 -7.62,-3.81; 2 -5.08,-3.81; 3 -2.54,-3.81; 4 0,-3.81; 5 2.54,-3.81; 6 5.08,-3.81; 7 7.62,-3.81; 8 7.62,3.81; 9 5.08,3.81; 10 2.54,3.81; 11 0,3.81; 12 -2.54,3.81; 13 -5.08,3.81; 14 -7.62,3.81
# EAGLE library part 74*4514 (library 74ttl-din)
1 of 16 noninverting DECODER/DEMULTIPLEXER

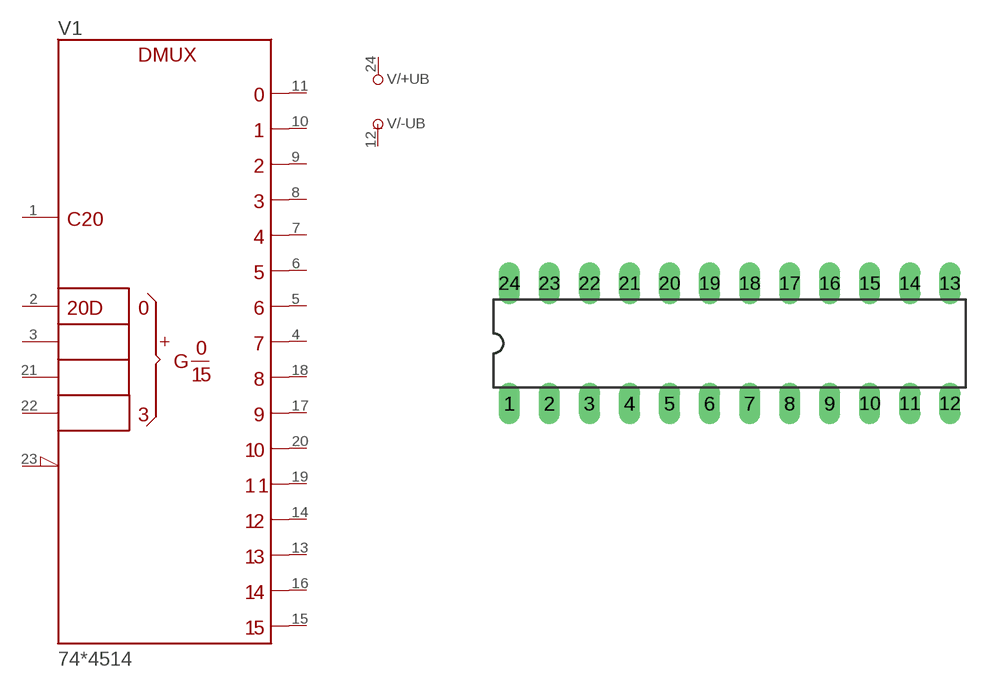
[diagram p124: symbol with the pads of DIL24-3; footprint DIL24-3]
Designator prefix V; gates /+UB=+UB /-UB=-UB 1=4514

## 744514N  [DIL24-3]
1  1:LE  in
2  1:A  in
3  1:B  in
4  1:Y7  out
5  1:Y6  out
6  1:Y5  out
7  1:Y4  out
8  1:Y3  out
9  1:Y2  out
10  1:Y1  out
11  1:Y0  out
12  /-UB:-UB  pwr
13  1:Y13  out
14  1:Y12  out
15  1:Y15  out
16  1:Y14  out
17  1:Y9  out
18  1:Y8  out
19  1:Y11  out
20  1:Y10  out
21  1:C  in
22  1:D  in
23  1:!G  in
24  /+UB:+UB  pwr

## Footprint DIL24-3 (pad centres in mm)
Dual In Line Package 0.3 inch
drill 0.813 long: 1 -13.97,-3.81; 2 -11.43,-3.81; 3 -8.89,-3.81; 4 -6.35,-3.81; 5 -3.81,-3.81; 6 -1.27,-3.81; 7 1.27,-3.81; 8 3.81,-3.81; 9 6.35,-3.81; 10 8.89,-3.81; 11 11.43,-3.81; 12 13.97,-3.81; 13 13.97,3.81; 14 11.43,3.81; 15 8.89,3.81; 16 6.35,3.81; 17 3.81,3.81; 18 1.27,3.81; 19 -1.27,3.81; 20 -3.81,3.81; 21 -6.35,3.81; 22 -8.89,3.81; 23 -11.43,3.81; 24 -13.97,3.81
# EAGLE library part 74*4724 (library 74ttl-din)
8 Bit Addressable LATCH

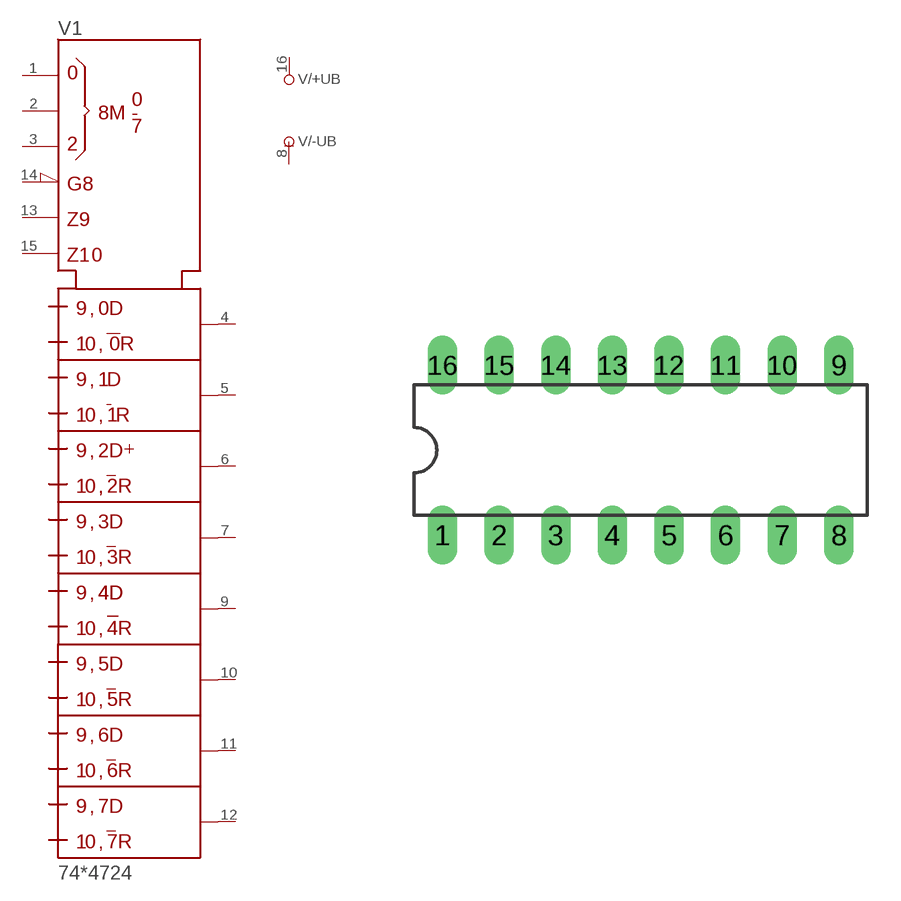
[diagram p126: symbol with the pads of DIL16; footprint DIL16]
Designator prefix V; gates /+UB=+UB /-UB=-UB 1=4724

## 744724N  [DIL16]
1  1:S0  in
2  1:S1  in
3  1:S2  in
4  1:Q0  out
5  1:Q1  out
6  1:Q2  out
7  1:Q3  out
8  /-UB:-UB  pwr
9  1:Q4  out
10  1:Q5  out
11  1:Q6  out
12  1:Q7  out
13  1:D  in
14  1:!G  in
15  1:CLR  in
16  /+UB:+UB  pwr

## Footprint DIL16 (pad centres in mm)
Dual In Line Package
drill 0.813 long: 1 -8.89,-3.81; 2 -6.35,-3.81; 3 -3.81,-3.81; 4 -1.27,-3.81; 5 1.27,-3.81; 6 3.81,-3.81; 7 6.35,-3.81; 8 8.89,-3.81; 9 8.89,3.81; 10 6.35,3.81; 11 3.81,3.81; 12 1.27,3.81; 13 -1.27,3.81; 14 -3.81,3.81; 15 -6.35,3.81; 16 -8.89,3.81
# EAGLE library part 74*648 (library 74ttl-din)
8-bit inverting TRANSCEIVER, 3-state

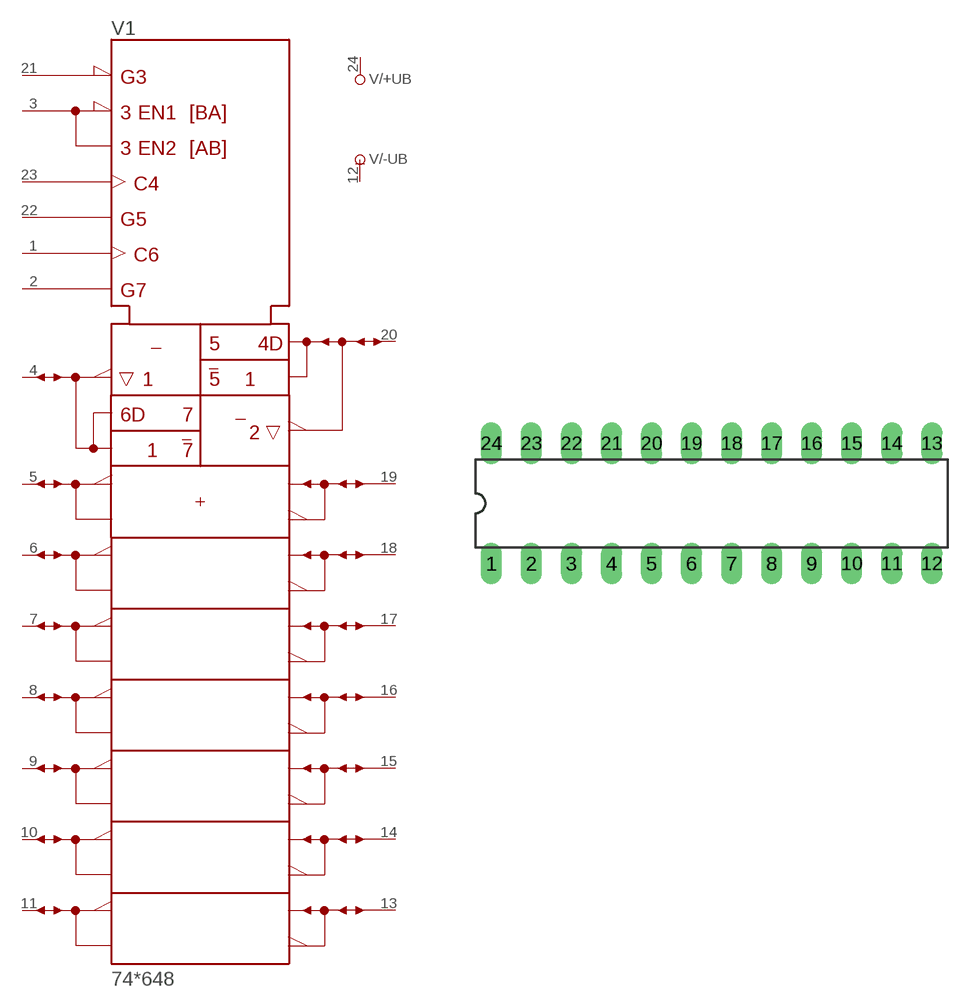
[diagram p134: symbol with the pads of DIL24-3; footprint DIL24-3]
Designator prefix V; gates /+UB=+UB /-UB=-UB 1=648

## 74648N  [DIL24-3]
1  1:CAB  in
2  1:SAB  in
3  1:DIR  in
4  1:A1
5  1:A2
6  1:A3
7  1:A4
8  1:A5
9  1:A6
10  1:A7
11  1:A8
12  /-UB:-UB  pwr
13  1:B8
14  1:B7
15  1:B6
16  1:B5
17  1:B4
18  1:B3
19  1:B2
20  1:B1
21  1:!G  in
22  1:SBA  in
23  1:CBA  in
24  /+UB:+UB  pwr

## Footprint DIL24-3 (pad centres in mm)
Dual In Line Package 0.3 inch
drill 0.813 long: 1 -13.97,-3.81; 2 -11.43,-3.81; 3 -8.89,-3.81; 4 -6.35,-3.81; 5 -3.81,-3.81; 6 -1.27,-3.81; 7 1.27,-3.81; 8 3.81,-3.81; 9 6.35,-3.81; 10 8.89,-3.81; 11 11.43,-3.81; 12 13.97,-3.81; 13 13.97,3.81; 14 11.43,3.81; 15 8.89,3.81; 16 6.35,3.81; 17 3.81,3.81; 18 1.27,3.81; 19 -1.27,3.81; 20 -3.81,3.81; 21 -6.35,3.81; 22 -8.89,3.81; 23 -11.43,3.81; 24 -13.97,3.81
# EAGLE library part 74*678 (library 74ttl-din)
16-bit address COMPARATOR, latch

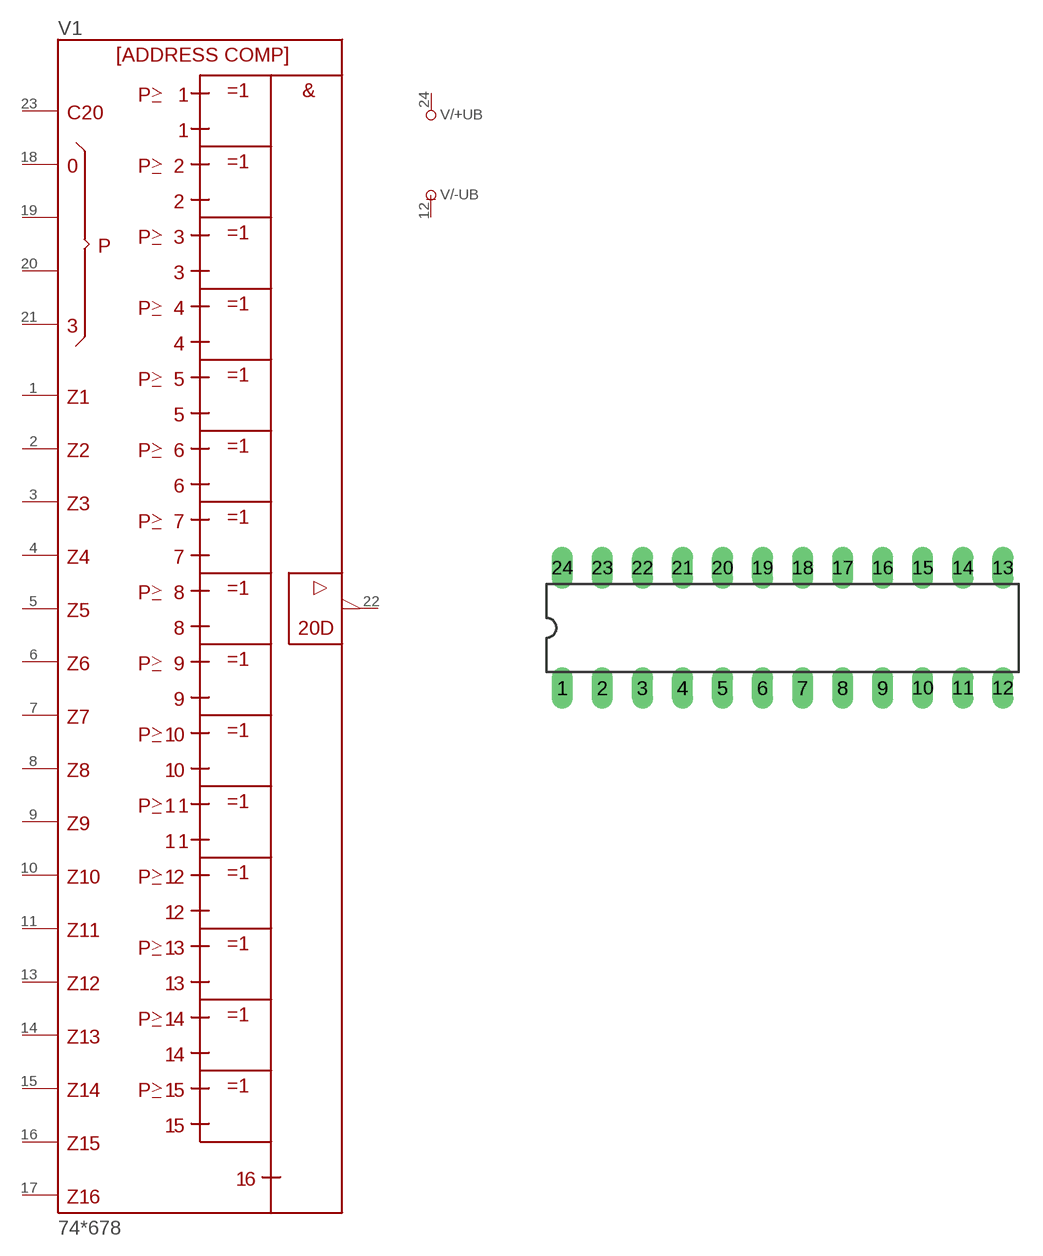
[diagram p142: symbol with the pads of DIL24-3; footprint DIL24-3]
Designator prefix V; gates /+UB=+UB /-UB=-UB 1=678

## 74678N  [DIL24-3]
1  1:A1  in
2  1:A2  in
3  1:A3  in
4  1:A4  in
5  1:A5  in
6  1:A6  in
7  1:A7  in
8  1:A8  in
9  1:A9  in
10  1:A10  in
11  1:A11  in
12  /-UB:-UB  pwr
13  1:A12  in
14  1:A13  in
15  1:A14  in
16  1:A15  in
17  1:A16  in
18  1:P0  in
19  1:P1  in
20  1:P2  in
21  1:P3  in
22  1:Y  out
23  1:C  in
24  /+UB:+UB  pwr

## Footprint DIL24-3 (pad centres in mm)
Dual In Line Package 0.3 inch
drill 0.813 long: 1 -13.97,-3.81; 2 -11.43,-3.81; 3 -8.89,-3.81; 4 -6.35,-3.81; 5 -3.81,-3.81; 6 -1.27,-3.81; 7 1.27,-3.81; 8 3.81,-3.81; 9 6.35,-3.81; 10 8.89,-3.81; 11 11.43,-3.81; 12 13.97,-3.81; 13 13.97,3.81; 14 11.43,3.81; 15 8.89,3.81; 16 6.35,3.81; 17 3.81,3.81; 18 1.27,3.81; 19 -1.27,3.81; 20 -3.81,3.81; 21 -6.35,3.81; 22 -8.89,3.81; 23 -11.43,3.81; 24 -13.97,3.81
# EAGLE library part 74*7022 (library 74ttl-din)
Octal COUNTER/DIVIDER with 1-of-8 Decoded Outputs

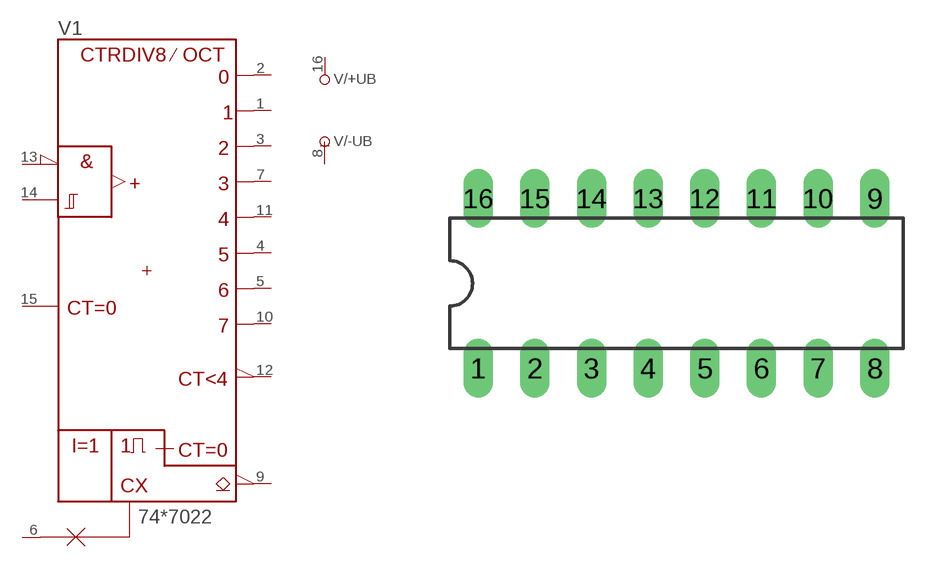
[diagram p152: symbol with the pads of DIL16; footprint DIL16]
Designator prefix V; gates /+UB=+UB /-UB=-UB 1=7022

## 747022N  [DIL16]
1  1:Y1  out
2  1:Y0  out
3  1:Y2  out
4  1:Y5  out
5  1:Y6  out
6  1:XCAP  pas
7  1:Y3  out
8  /-UB:-UB  pwr
9  1:!CLROUT  oc
10  1:Y7  out
11  1:Y4  out
12  1:CO  out
13  1:!CLKEN  in
14  1:CLK  in
15  1:CLR  in
16  /+UB:+UB  pwr

## Footprint DIL16 (pad centres in mm)
Dual In Line Package
drill 0.813 long: 1 -8.89,-3.81; 2 -6.35,-3.81; 3 -3.81,-3.81; 4 -1.27,-3.81; 5 1.27,-3.81; 6 3.81,-3.81; 7 6.35,-3.81; 8 8.89,-3.81; 9 8.89,3.81; 10 6.35,3.81; 11 3.81,3.81; 12 1.27,3.81; 13 -1.27,3.81; 14 -3.81,3.81; 15 -6.35,3.81; 16 -8.89,3.81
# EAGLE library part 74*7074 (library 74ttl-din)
Dual J-K FLIP FLOP, INVERTER/NOR/NAND

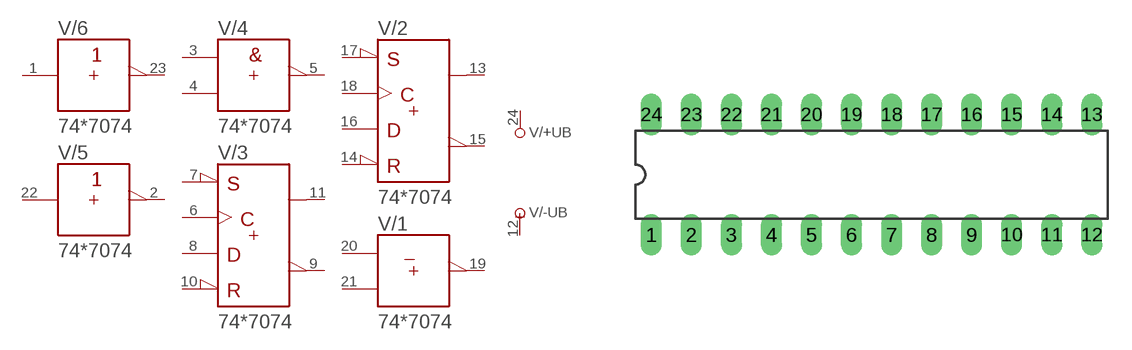
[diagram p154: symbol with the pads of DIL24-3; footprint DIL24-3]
Designator prefix V; gates /+UB=+UB /-UB=-UB /1=7074_6 /2=7074_5 /3=7074_4 /4=7074_3 /5=7074_2 /6=7074_1

## 747074N  [DIL24-3]
1  /6:A  in
2  /5:Y  out
3  /4:A  in
4  /4:B  in
5  /4:Y  out
6  /3:CLK  in
7  /3:!PRE  in
8  /3:D  in
9  /3:!Q  out
10  /3:!CLR  in
11  /3:Q  out
12  /-UB:-UB  pwr
13  /2:Q  out
14  /2:!CLR  in
15  /2:!Q  out
16  /2:D  in
17  /2:!PRE  in
18  /2:CLK  in
19  /1:Y  out
20  /1:A  in
21  /1:B  in
22  /5:A  in
23  /6:Y  out
24  /+UB:+UB  pwr

## Footprint DIL24-3 (pad centres in mm)
Dual In Line Package 0.3 inch
drill 0.813 long: 1 -13.97,-3.81; 2 -11.43,-3.81; 3 -8.89,-3.81; 4 -6.35,-3.81; 5 -3.81,-3.81; 6 -1.27,-3.81; 7 1.27,-3.81; 8 3.81,-3.81; 9 6.35,-3.81; 10 8.89,-3.81; 11 11.43,-3.81; 12 13.97,-3.81; 13 13.97,3.81; 14 11.43,3.81; 15 8.89,3.81; 16 6.35,3.81; 17 3.81,3.81; 18 1.27,3.81; 19 -1.27,3.81; 20 -3.81,3.81; 21 -6.35,3.81; 22 -8.89,3.81; 23 -11.43,3.81; 24 -13.97,3.81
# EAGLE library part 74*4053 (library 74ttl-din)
Triple 2-channel analog multiplexer/demultiplexer Philips Semiconductor

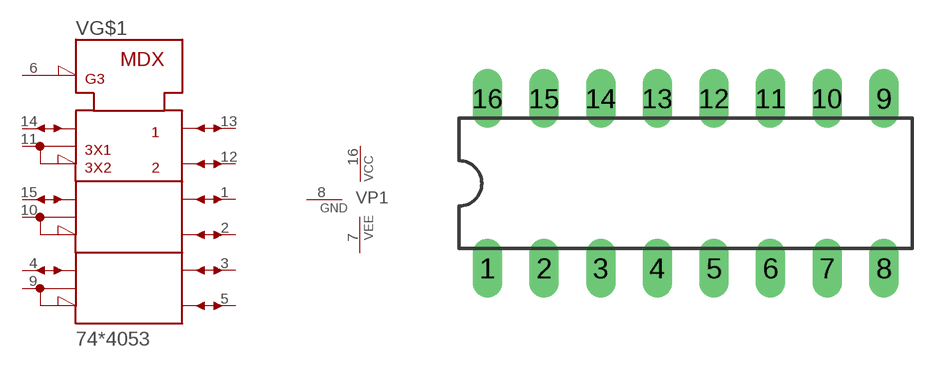
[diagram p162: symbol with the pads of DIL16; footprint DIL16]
Designator prefix V; gates G$1=4053 P1=PWRVCCGNDVEE

## 74HC4053P, 74HCT4053P  [DIL16]
1  G$1:1
2  G$1:2
3  G$1:3
4  G$1:4
5  G$1:5
6  G$1:!G  in
7  P1:VEE  pwr
8  P1:GND  pwr
9  G$1:9
10  G$1:10
11  G$1:11
12  G$1:12
13  G$1:13
14  G$1:14
15  G$1:15
16  P1:VCC  pwr

## Footprint DIL16 (pad centres in mm)
Dual In Line Package
drill 0.813 long: 1 -8.89,-3.81; 2 -6.35,-3.81; 3 -3.81,-3.81; 4 -1.27,-3.81; 5 1.27,-3.81; 6 3.81,-3.81; 7 6.35,-3.81; 8 8.89,-3.81; 9 8.89,3.81; 10 6.35,3.81; 11 3.81,3.81; 12 1.27,3.81; 13 -1.27,3.81; 14 -3.81,3.81; 15 -6.35,3.81; 16 -8.89,3.81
